VERSION 5.7 ;
BUSBITCHARS "[]" ;
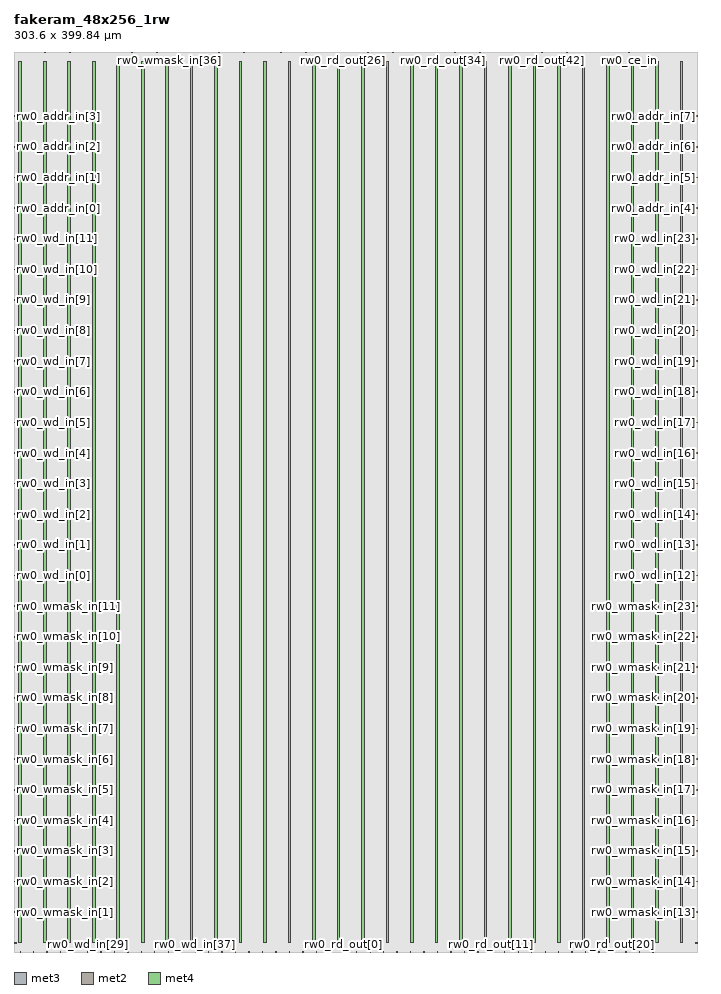
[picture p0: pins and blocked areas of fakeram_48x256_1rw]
MACRO fakeram_48x256_1rw
  FOREIGN fakeram_48x256_1rw 0 0 ;
  SYMMETRY X Y R90 ;
  SIZE 303.600 BY 399.840 ;
  CLASS BLOCK ;
  PIN rw0_wmask_in[0]
    DIRECTION INPUT ;
    USE SIGNAL ;
    SHAPE ABUTMENT ;
    PORT
      LAYER met3 ;
      RECT 0.000 3.930 0.900 4.230 ;
    END
  END rw0_wmask_in[0]
  PIN rw0_wmask_in[1]
    DIRECTION INPUT ;
    USE SIGNAL ;
    SHAPE ABUTMENT ;
    PORT
      LAYER met3 ;
      RECT 0.000 17.530 0.900 17.830 ;
    END
  END rw0_wmask_in[1]
  PIN rw0_wmask_in[2]
    DIRECTION INPUT ;
    USE SIGNAL ;
    SHAPE ABUTMENT ;
    PORT
      LAYER met3 ;
      RECT 0.000 31.130 0.900 31.430 ;
    END
  END rw0_wmask_in[2]
  PIN rw0_wmask_in[3]
    DIRECTION INPUT ;
    USE SIGNAL ;
    SHAPE ABUTMENT ;
    PORT
      LAYER met3 ;
      RECT 0.000 44.730 0.900 45.030 ;
    END
  END rw0_wmask_in[3]
  PIN rw0_wmask_in[4]
    DIRECTION INPUT ;
    USE SIGNAL ;
    SHAPE ABUTMENT ;
    PORT
      LAYER met3 ;
      RECT 0.000 58.330 0.900 58.630 ;
    END
  END rw0_wmask_in[4]
  PIN rw0_wmask_in[5]
    DIRECTION INPUT ;
    USE SIGNAL ;
    SHAPE ABUTMENT ;
    PORT
      LAYER met3 ;
      RECT 0.000 71.930 0.900 72.230 ;
    END
  END rw0_wmask_in[5]
  PIN rw0_wmask_in[6]
    DIRECTION INPUT ;
    USE SIGNAL ;
    SHAPE ABUTMENT ;
    PORT
      LAYER met3 ;
      RECT 0.000 85.530 0.900 85.830 ;
    END
  END rw0_wmask_in[6]
  PIN rw0_wmask_in[7]
    DIRECTION INPUT ;
    USE SIGNAL ;
    SHAPE ABUTMENT ;
    PORT
      LAYER met3 ;
      RECT 0.000 99.130 0.900 99.430 ;
    END
  END rw0_wmask_in[7]
  PIN rw0_wmask_in[8]
    DIRECTION INPUT ;
    USE SIGNAL ;
    SHAPE ABUTMENT ;
    PORT
      LAYER met3 ;
      RECT 0.000 112.730 0.900 113.030 ;
    END
  END rw0_wmask_in[8]
  PIN rw0_wmask_in[9]
    DIRECTION INPUT ;
    USE SIGNAL ;
    SHAPE ABUTMENT ;
    PORT
      LAYER met3 ;
      RECT 0.000 126.330 0.900 126.630 ;
    END
  END rw0_wmask_in[9]
  PIN rw0_wmask_in[10]
    DIRECTION INPUT ;
    USE SIGNAL ;
    SHAPE ABUTMENT ;
    PORT
      LAYER met3 ;
      RECT 0.000 139.930 0.900 140.230 ;
    END
  END rw0_wmask_in[10]
  PIN rw0_wmask_in[11]
    DIRECTION INPUT ;
    USE SIGNAL ;
    SHAPE ABUTMENT ;
    PORT
      LAYER met3 ;
      RECT 0.000 153.530 0.900 153.830 ;
    END
  END rw0_wmask_in[11]
  PIN rw0_wmask_in[12]
    DIRECTION INPUT ;
    USE SIGNAL ;
    SHAPE ABUTMENT ;
    PORT
      LAYER met3 ;
      RECT 302.700 3.930 303.600 4.230 ;
    END
  END rw0_wmask_in[12]
  PIN rw0_wmask_in[13]
    DIRECTION INPUT ;
    USE SIGNAL ;
    SHAPE ABUTMENT ;
    PORT
      LAYER met3 ;
      RECT 302.700 17.530 303.600 17.830 ;
    END
  END rw0_wmask_in[13]
  PIN rw0_wmask_in[14]
    DIRECTION INPUT ;
    USE SIGNAL ;
    SHAPE ABUTMENT ;
    PORT
      LAYER met3 ;
      RECT 302.700 31.130 303.600 31.430 ;
    END
  END rw0_wmask_in[14]
  PIN rw0_wmask_in[15]
    DIRECTION INPUT ;
    USE SIGNAL ;
    SHAPE ABUTMENT ;
    PORT
      LAYER met3 ;
      RECT 302.700 44.730 303.600 45.030 ;
    END
  END rw0_wmask_in[15]
  PIN rw0_wmask_in[16]
    DIRECTION INPUT ;
    USE SIGNAL ;
    SHAPE ABUTMENT ;
    PORT
      LAYER met3 ;
      RECT 302.700 58.330 303.600 58.630 ;
    END
  END rw0_wmask_in[16]
  PIN rw0_wmask_in[17]
    DIRECTION INPUT ;
    USE SIGNAL ;
    SHAPE ABUTMENT ;
    PORT
      LAYER met3 ;
      RECT 302.700 71.930 303.600 72.230 ;
    END
  END rw0_wmask_in[17]
  PIN rw0_wmask_in[18]
    DIRECTION INPUT ;
    USE SIGNAL ;
    SHAPE ABUTMENT ;
    PORT
      LAYER met3 ;
      RECT 302.700 85.530 303.600 85.830 ;
    END
  END rw0_wmask_in[18]
  PIN rw0_wmask_in[19]
    DIRECTION INPUT ;
    USE SIGNAL ;
    SHAPE ABUTMENT ;
    PORT
      LAYER met3 ;
      RECT 302.700 99.130 303.600 99.430 ;
    END
  END rw0_wmask_in[19]
  PIN rw0_wmask_in[20]
    DIRECTION INPUT ;
    USE SIGNAL ;
    SHAPE ABUTMENT ;
    PORT
      LAYER met3 ;
      RECT 302.700 112.730 303.600 113.030 ;
    END
  END rw0_wmask_in[20]
  PIN rw0_wmask_in[21]
    DIRECTION INPUT ;
    USE SIGNAL ;
    SHAPE ABUTMENT ;
    PORT
      LAYER met3 ;
      RECT 302.700 126.330 303.600 126.630 ;
    END
  END rw0_wmask_in[21]
  PIN rw0_wmask_in[22]
    DIRECTION INPUT ;
    USE SIGNAL ;
    SHAPE ABUTMENT ;
    PORT
      LAYER met3 ;
      RECT 302.700 139.930 303.600 140.230 ;
    END
  END rw0_wmask_in[22]
  PIN rw0_wmask_in[23]
    DIRECTION INPUT ;
    USE SIGNAL ;
    SHAPE ABUTMENT ;
    PORT
      LAYER met3 ;
      RECT 302.700 153.530 303.600 153.830 ;
    END
  END rw0_wmask_in[23]
  PIN rw0_wmask_in[24]
    DIRECTION INPUT ;
    USE SIGNAL ;
    SHAPE ABUTMENT ;
    PORT
      LAYER met2 ;
      RECT 2.690 399.420 2.830 399.840 ;
    END
  END rw0_wmask_in[24]
  PIN rw0_wmask_in[25]
    DIRECTION INPUT ;
    USE SIGNAL ;
    SHAPE ABUTMENT ;
    PORT
      LAYER met2 ;
      RECT 8.210 399.420 8.350 399.840 ;
    END
  END rw0_wmask_in[25]
  PIN rw0_wmask_in[26]
    DIRECTION INPUT ;
    USE SIGNAL ;
    SHAPE ABUTMENT ;
    PORT
      LAYER met2 ;
      RECT 13.730 399.420 13.870 399.840 ;
    END
  END rw0_wmask_in[26]
  PIN rw0_wmask_in[27]
    DIRECTION INPUT ;
    USE SIGNAL ;
    SHAPE ABUTMENT ;
    PORT
      LAYER met2 ;
      RECT 19.250 399.420 19.390 399.840 ;
    END
  END rw0_wmask_in[27]
  PIN rw0_wmask_in[28]
    DIRECTION INPUT ;
    USE SIGNAL ;
    SHAPE ABUTMENT ;
    PORT
      LAYER met2 ;
      RECT 24.770 399.420 24.910 399.840 ;
    END
  END rw0_wmask_in[28]
  PIN rw0_wmask_in[29]
    DIRECTION INPUT ;
    USE SIGNAL ;
    SHAPE ABUTMENT ;
    PORT
      LAYER met2 ;
      RECT 30.290 399.420 30.430 399.840 ;
    END
  END rw0_wmask_in[29]
  PIN rw0_wmask_in[30]
    DIRECTION INPUT ;
    USE SIGNAL ;
    SHAPE ABUTMENT ;
    PORT
      LAYER met2 ;
      RECT 35.810 399.420 35.950 399.840 ;
    END
  END rw0_wmask_in[30]
  PIN rw0_wmask_in[31]
    DIRECTION INPUT ;
    USE SIGNAL ;
    SHAPE ABUTMENT ;
    PORT
      LAYER met2 ;
      RECT 41.330 399.420 41.470 399.840 ;
    END
  END rw0_wmask_in[31]
  PIN rw0_wmask_in[32]
    DIRECTION INPUT ;
    USE SIGNAL ;
    SHAPE ABUTMENT ;
    PORT
      LAYER met2 ;
      RECT 46.850 399.420 46.990 399.840 ;
    END
  END rw0_wmask_in[32]
  PIN rw0_wmask_in[33]
    DIRECTION INPUT ;
    USE SIGNAL ;
    SHAPE ABUTMENT ;
    PORT
      LAYER met2 ;
      RECT 52.370 399.420 52.510 399.840 ;
    END
  END rw0_wmask_in[33]
  PIN rw0_wmask_in[34]
    DIRECTION INPUT ;
    USE SIGNAL ;
    SHAPE ABUTMENT ;
    PORT
      LAYER met2 ;
      RECT 57.890 399.420 58.030 399.840 ;
    END
  END rw0_wmask_in[34]
  PIN rw0_wmask_in[35]
    DIRECTION INPUT ;
    USE SIGNAL ;
    SHAPE ABUTMENT ;
    PORT
      LAYER met2 ;
      RECT 63.410 399.420 63.550 399.840 ;
    END
  END rw0_wmask_in[35]
  PIN rw0_wmask_in[36]
    DIRECTION INPUT ;
    USE SIGNAL ;
    SHAPE ABUTMENT ;
    PORT
      LAYER met2 ;
      RECT 68.930 399.420 69.070 399.840 ;
    END
  END rw0_wmask_in[36]
  PIN rw0_wmask_in[37]
    DIRECTION INPUT ;
    USE SIGNAL ;
    SHAPE ABUTMENT ;
    PORT
      LAYER met2 ;
      RECT 74.450 399.420 74.590 399.840 ;
    END
  END rw0_wmask_in[37]
  PIN rw0_wmask_in[38]
    DIRECTION INPUT ;
    USE SIGNAL ;
    SHAPE ABUTMENT ;
    PORT
      LAYER met2 ;
      RECT 79.970 399.420 80.110 399.840 ;
    END
  END rw0_wmask_in[38]
  PIN rw0_wmask_in[39]
    DIRECTION INPUT ;
    USE SIGNAL ;
    SHAPE ABUTMENT ;
    PORT
      LAYER met2 ;
      RECT 85.490 399.420 85.630 399.840 ;
    END
  END rw0_wmask_in[39]
  PIN rw0_wmask_in[40]
    DIRECTION INPUT ;
    USE SIGNAL ;
    SHAPE ABUTMENT ;
    PORT
      LAYER met2 ;
      RECT 91.010 399.420 91.150 399.840 ;
    END
  END rw0_wmask_in[40]
  PIN rw0_wmask_in[41]
    DIRECTION INPUT ;
    USE SIGNAL ;
    SHAPE ABUTMENT ;
    PORT
      LAYER met2 ;
      RECT 96.530 399.420 96.670 399.840 ;
    END
  END rw0_wmask_in[41]
  PIN rw0_wmask_in[42]
    DIRECTION INPUT ;
    USE SIGNAL ;
    SHAPE ABUTMENT ;
    PORT
      LAYER met2 ;
      RECT 102.050 399.420 102.190 399.840 ;
    END
  END rw0_wmask_in[42]
  PIN rw0_wmask_in[43]
    DIRECTION INPUT ;
    USE SIGNAL ;
    SHAPE ABUTMENT ;
    PORT
      LAYER met2 ;
      RECT 107.570 399.420 107.710 399.840 ;
    END
  END rw0_wmask_in[43]
  PIN rw0_wmask_in[44]
    DIRECTION INPUT ;
    USE SIGNAL ;
    SHAPE ABUTMENT ;
    PORT
      LAYER met2 ;
      RECT 113.090 399.420 113.230 399.840 ;
    END
  END rw0_wmask_in[44]
  PIN rw0_wmask_in[45]
    DIRECTION INPUT ;
    USE SIGNAL ;
    SHAPE ABUTMENT ;
    PORT
      LAYER met2 ;
      RECT 118.610 399.420 118.750 399.840 ;
    END
  END rw0_wmask_in[45]
  PIN rw0_wmask_in[46]
    DIRECTION INPUT ;
    USE SIGNAL ;
    SHAPE ABUTMENT ;
    PORT
      LAYER met2 ;
      RECT 124.130 399.420 124.270 399.840 ;
    END
  END rw0_wmask_in[46]
  PIN rw0_wmask_in[47]
    DIRECTION INPUT ;
    USE SIGNAL ;
    SHAPE ABUTMENT ;
    PORT
      LAYER met2 ;
      RECT 129.650 399.420 129.790 399.840 ;
    END
  END rw0_wmask_in[47]
  PIN rw0_wd_in[0]
    DIRECTION INPUT ;
    USE SIGNAL ;
    SHAPE ABUTMENT ;
    PORT
      LAYER met3 ;
      RECT 0.000 167.130 0.900 167.430 ;
    END
  END rw0_wd_in[0]
  PIN rw0_wd_in[1]
    DIRECTION INPUT ;
    USE SIGNAL ;
    SHAPE ABUTMENT ;
    PORT
      LAYER met3 ;
      RECT 0.000 180.730 0.900 181.030 ;
    END
  END rw0_wd_in[1]
  PIN rw0_wd_in[2]
    DIRECTION INPUT ;
    USE SIGNAL ;
    SHAPE ABUTMENT ;
    PORT
      LAYER met3 ;
      RECT 0.000 194.330 0.900 194.630 ;
    END
  END rw0_wd_in[2]
  PIN rw0_wd_in[3]
    DIRECTION INPUT ;
    USE SIGNAL ;
    SHAPE ABUTMENT ;
    PORT
      LAYER met3 ;
      RECT 0.000 207.930 0.900 208.230 ;
    END
  END rw0_wd_in[3]
  PIN rw0_wd_in[4]
    DIRECTION INPUT ;
    USE SIGNAL ;
    SHAPE ABUTMENT ;
    PORT
      LAYER met3 ;
      RECT 0.000 221.530 0.900 221.830 ;
    END
  END rw0_wd_in[4]
  PIN rw0_wd_in[5]
    DIRECTION INPUT ;
    USE SIGNAL ;
    SHAPE ABUTMENT ;
    PORT
      LAYER met3 ;
      RECT 0.000 235.130 0.900 235.430 ;
    END
  END rw0_wd_in[5]
  PIN rw0_wd_in[6]
    DIRECTION INPUT ;
    USE SIGNAL ;
    SHAPE ABUTMENT ;
    PORT
      LAYER met3 ;
      RECT 0.000 248.730 0.900 249.030 ;
    END
  END rw0_wd_in[6]
  PIN rw0_wd_in[7]
    DIRECTION INPUT ;
    USE SIGNAL ;
    SHAPE ABUTMENT ;
    PORT
      LAYER met3 ;
      RECT 0.000 262.330 0.900 262.630 ;
    END
  END rw0_wd_in[7]
  PIN rw0_wd_in[8]
    DIRECTION INPUT ;
    USE SIGNAL ;
    SHAPE ABUTMENT ;
    PORT
      LAYER met3 ;
      RECT 0.000 275.930 0.900 276.230 ;
    END
  END rw0_wd_in[8]
  PIN rw0_wd_in[9]
    DIRECTION INPUT ;
    USE SIGNAL ;
    SHAPE ABUTMENT ;
    PORT
      LAYER met3 ;
      RECT 0.000 289.530 0.900 289.830 ;
    END
  END rw0_wd_in[9]
  PIN rw0_wd_in[10]
    DIRECTION INPUT ;
    USE SIGNAL ;
    SHAPE ABUTMENT ;
    PORT
      LAYER met3 ;
      RECT 0.000 303.130 0.900 303.430 ;
    END
  END rw0_wd_in[10]
  PIN rw0_wd_in[11]
    DIRECTION INPUT ;
    USE SIGNAL ;
    SHAPE ABUTMENT ;
    PORT
      LAYER met3 ;
      RECT 0.000 316.730 0.900 317.030 ;
    END
  END rw0_wd_in[11]
  PIN rw0_wd_in[12]
    DIRECTION INPUT ;
    USE SIGNAL ;
    SHAPE ABUTMENT ;
    PORT
      LAYER met3 ;
      RECT 302.700 167.130 303.600 167.430 ;
    END
  END rw0_wd_in[12]
  PIN rw0_wd_in[13]
    DIRECTION INPUT ;
    USE SIGNAL ;
    SHAPE ABUTMENT ;
    PORT
      LAYER met3 ;
      RECT 302.700 180.730 303.600 181.030 ;
    END
  END rw0_wd_in[13]
  PIN rw0_wd_in[14]
    DIRECTION INPUT ;
    USE SIGNAL ;
    SHAPE ABUTMENT ;
    PORT
      LAYER met3 ;
      RECT 302.700 194.330 303.600 194.630 ;
    END
  END rw0_wd_in[14]
  PIN rw0_wd_in[15]
    DIRECTION INPUT ;
    USE SIGNAL ;
    SHAPE ABUTMENT ;
    PORT
      LAYER met3 ;
      RECT 302.700 207.930 303.600 208.230 ;
    END
  END rw0_wd_in[15]
  PIN rw0_wd_in[16]
    DIRECTION INPUT ;
    USE SIGNAL ;
    SHAPE ABUTMENT ;
    PORT
      LAYER met3 ;
      RECT 302.700 221.530 303.600 221.830 ;
    END
  END rw0_wd_in[16]
  PIN rw0_wd_in[17]
    DIRECTION INPUT ;
    USE SIGNAL ;
    SHAPE ABUTMENT ;
    PORT
      LAYER met3 ;
      RECT 302.700 235.130 303.600 235.430 ;
    END
  END rw0_wd_in[17]
  PIN rw0_wd_in[18]
    DIRECTION INPUT ;
    USE SIGNAL ;
    SHAPE ABUTMENT ;
    PORT
      LAYER met3 ;
      RECT 302.700 248.730 303.600 249.030 ;
    END
  END rw0_wd_in[18]
  PIN rw0_wd_in[19]
    DIRECTION INPUT ;
    USE SIGNAL ;
    SHAPE ABUTMENT ;
    PORT
      LAYER met3 ;
      RECT 302.700 262.330 303.600 262.630 ;
    END
  END rw0_wd_in[19]
  PIN rw0_wd_in[20]
    DIRECTION INPUT ;
    USE SIGNAL ;
    SHAPE ABUTMENT ;
    PORT
      LAYER met3 ;
      RECT 302.700 275.930 303.600 276.230 ;
    END
  END rw0_wd_in[20]
  PIN rw0_wd_in[21]
    DIRECTION INPUT ;
    USE SIGNAL ;
    SHAPE ABUTMENT ;
    PORT
      LAYER met3 ;
      RECT 302.700 289.530 303.600 289.830 ;
    END
  END rw0_wd_in[21]
  PIN rw0_wd_in[22]
    DIRECTION INPUT ;
    USE SIGNAL ;
    SHAPE ABUTMENT ;
    PORT
      LAYER met3 ;
      RECT 302.700 303.130 303.600 303.430 ;
    END
  END rw0_wd_in[22]
  PIN rw0_wd_in[23]
    DIRECTION INPUT ;
    USE SIGNAL ;
    SHAPE ABUTMENT ;
    PORT
      LAYER met3 ;
      RECT 302.700 316.730 303.600 317.030 ;
    END
  END rw0_wd_in[23]
  PIN rw0_wd_in[24]
    DIRECTION OUTPUT ;
    USE SIGNAL ;
    SHAPE ABUTMENT ;
    PORT
      LAYER met2 ;
      RECT 2.690 0.000 2.830 0.420 ;
    END
  END rw0_wd_in[24]
  PIN rw0_wd_in[25]
    DIRECTION OUTPUT ;
    USE SIGNAL ;
    SHAPE ABUTMENT ;
    PORT
      LAYER met2 ;
      RECT 8.670 0.000 8.810 0.420 ;
    END
  END rw0_wd_in[25]
  PIN rw0_wd_in[26]
    DIRECTION OUTPUT ;
    USE SIGNAL ;
    SHAPE ABUTMENT ;
    PORT
      LAYER met2 ;
      RECT 14.650 0.000 14.790 0.420 ;
    END
  END rw0_wd_in[26]
  PIN rw0_wd_in[27]
    DIRECTION OUTPUT ;
    USE SIGNAL ;
    SHAPE ABUTMENT ;
    PORT
      LAYER met2 ;
      RECT 20.630 0.000 20.770 0.420 ;
    END
  END rw0_wd_in[27]
  PIN rw0_wd_in[28]
    DIRECTION OUTPUT ;
    USE SIGNAL ;
    SHAPE ABUTMENT ;
    PORT
      LAYER met2 ;
      RECT 26.610 0.000 26.750 0.420 ;
    END
  END rw0_wd_in[28]
  PIN rw0_wd_in[29]
    DIRECTION OUTPUT ;
    USE SIGNAL ;
    SHAPE ABUTMENT ;
    PORT
      LAYER met2 ;
      RECT 32.590 0.000 32.730 0.420 ;
    END
  END rw0_wd_in[29]
  PIN rw0_wd_in[30]
    DIRECTION OUTPUT ;
    USE SIGNAL ;
    SHAPE ABUTMENT ;
    PORT
      LAYER met2 ;
      RECT 38.570 0.000 38.710 0.420 ;
    END
  END rw0_wd_in[30]
  PIN rw0_wd_in[31]
    DIRECTION OUTPUT ;
    USE SIGNAL ;
    SHAPE ABUTMENT ;
    PORT
      LAYER met2 ;
      RECT 44.550 0.000 44.690 0.420 ;
    END
  END rw0_wd_in[31]
  PIN rw0_wd_in[32]
    DIRECTION OUTPUT ;
    USE SIGNAL ;
    SHAPE ABUTMENT ;
    PORT
      LAYER met2 ;
      RECT 50.530 0.000 50.670 0.420 ;
    END
  END rw0_wd_in[32]
  PIN rw0_wd_in[33]
    DIRECTION OUTPUT ;
    USE SIGNAL ;
    SHAPE ABUTMENT ;
    PORT
      LAYER met2 ;
      RECT 56.510 0.000 56.650 0.420 ;
    END
  END rw0_wd_in[33]
  PIN rw0_wd_in[34]
    DIRECTION OUTPUT ;
    USE SIGNAL ;
    SHAPE ABUTMENT ;
    PORT
      LAYER met2 ;
      RECT 62.490 0.000 62.630 0.420 ;
    END
  END rw0_wd_in[34]
  PIN rw0_wd_in[35]
    DIRECTION OUTPUT ;
    USE SIGNAL ;
    SHAPE ABUTMENT ;
    PORT
      LAYER met2 ;
      RECT 68.470 0.000 68.610 0.420 ;
    END
  END rw0_wd_in[35]
  PIN rw0_wd_in[36]
    DIRECTION OUTPUT ;
    USE SIGNAL ;
    SHAPE ABUTMENT ;
    PORT
      LAYER met2 ;
      RECT 74.450 0.000 74.590 0.420 ;
    END
  END rw0_wd_in[36]
  PIN rw0_wd_in[37]
    DIRECTION OUTPUT ;
    USE SIGNAL ;
    SHAPE ABUTMENT ;
    PORT
      LAYER met2 ;
      RECT 80.430 0.000 80.570 0.420 ;
    END
  END rw0_wd_in[37]
  PIN rw0_wd_in[38]
    DIRECTION OUTPUT ;
    USE SIGNAL ;
    SHAPE ABUTMENT ;
    PORT
      LAYER met2 ;
      RECT 86.410 0.000 86.550 0.420 ;
    END
  END rw0_wd_in[38]
  PIN rw0_wd_in[39]
    DIRECTION OUTPUT ;
    USE SIGNAL ;
    SHAPE ABUTMENT ;
    PORT
      LAYER met2 ;
      RECT 92.390 0.000 92.530 0.420 ;
    END
  END rw0_wd_in[39]
  PIN rw0_wd_in[40]
    DIRECTION OUTPUT ;
    USE SIGNAL ;
    SHAPE ABUTMENT ;
    PORT
      LAYER met2 ;
      RECT 98.370 0.000 98.510 0.420 ;
    END
  END rw0_wd_in[40]
  PIN rw0_wd_in[41]
    DIRECTION OUTPUT ;
    USE SIGNAL ;
    SHAPE ABUTMENT ;
    PORT
      LAYER met2 ;
      RECT 104.350 0.000 104.490 0.420 ;
    END
  END rw0_wd_in[41]
  PIN rw0_wd_in[42]
    DIRECTION OUTPUT ;
    USE SIGNAL ;
    SHAPE ABUTMENT ;
    PORT
      LAYER met2 ;
      RECT 110.330 0.000 110.470 0.420 ;
    END
  END rw0_wd_in[42]
  PIN rw0_wd_in[43]
    DIRECTION OUTPUT ;
    USE SIGNAL ;
    SHAPE ABUTMENT ;
    PORT
      LAYER met2 ;
      RECT 116.310 0.000 116.450 0.420 ;
    END
  END rw0_wd_in[43]
  PIN rw0_wd_in[44]
    DIRECTION OUTPUT ;
    USE SIGNAL ;
    SHAPE ABUTMENT ;
    PORT
      LAYER met2 ;
      RECT 122.290 0.000 122.430 0.420 ;
    END
  END rw0_wd_in[44]
  PIN rw0_wd_in[45]
    DIRECTION OUTPUT ;
    USE SIGNAL ;
    SHAPE ABUTMENT ;
    PORT
      LAYER met2 ;
      RECT 128.270 0.000 128.410 0.420 ;
    END
  END rw0_wd_in[45]
  PIN rw0_wd_in[46]
    DIRECTION OUTPUT ;
    USE SIGNAL ;
    SHAPE ABUTMENT ;
    PORT
      LAYER met2 ;
      RECT 134.250 0.000 134.390 0.420 ;
    END
  END rw0_wd_in[46]
  PIN rw0_wd_in[47]
    DIRECTION OUTPUT ;
    USE SIGNAL ;
    SHAPE ABUTMENT ;
    PORT
      LAYER met2 ;
      RECT 140.230 0.000 140.370 0.420 ;
    END
  END rw0_wd_in[47]
  PIN rw0_rd_out[0]
    DIRECTION OUTPUT ;
    USE SIGNAL ;
    SHAPE ABUTMENT ;
    PORT
      LAYER met2 ;
      RECT 146.210 0.000 146.350 0.420 ;
    END
  END rw0_rd_out[0]
  PIN rw0_rd_out[1]
    DIRECTION OUTPUT ;
    USE SIGNAL ;
    SHAPE ABUTMENT ;
    PORT
      LAYER met2 ;
      RECT 152.190 0.000 152.330 0.420 ;
    END
  END rw0_rd_out[1]
  PIN rw0_rd_out[2]
    DIRECTION OUTPUT ;
    USE SIGNAL ;
    SHAPE ABUTMENT ;
    PORT
      LAYER met2 ;
      RECT 158.170 0.000 158.310 0.420 ;
    END
  END rw0_rd_out[2]
  PIN rw0_rd_out[3]
    DIRECTION OUTPUT ;
    USE SIGNAL ;
    SHAPE ABUTMENT ;
    PORT
      LAYER met2 ;
      RECT 164.150 0.000 164.290 0.420 ;
    END
  END rw0_rd_out[3]
  PIN rw0_rd_out[4]
    DIRECTION OUTPUT ;
    USE SIGNAL ;
    SHAPE ABUTMENT ;
    PORT
      LAYER met2 ;
      RECT 170.130 0.000 170.270 0.420 ;
    END
  END rw0_rd_out[4]
  PIN rw0_rd_out[5]
    DIRECTION OUTPUT ;
    USE SIGNAL ;
    SHAPE ABUTMENT ;
    PORT
      LAYER met2 ;
      RECT 176.110 0.000 176.250 0.420 ;
    END
  END rw0_rd_out[5]
  PIN rw0_rd_out[6]
    DIRECTION OUTPUT ;
    USE SIGNAL ;
    SHAPE ABUTMENT ;
    PORT
      LAYER met2 ;
      RECT 182.090 0.000 182.230 0.420 ;
    END
  END rw0_rd_out[6]
  PIN rw0_rd_out[7]
    DIRECTION OUTPUT ;
    USE SIGNAL ;
    SHAPE ABUTMENT ;
    PORT
      LAYER met2 ;
      RECT 188.070 0.000 188.210 0.420 ;
    END
  END rw0_rd_out[7]
  PIN rw0_rd_out[8]
    DIRECTION OUTPUT ;
    USE SIGNAL ;
    SHAPE ABUTMENT ;
    PORT
      LAYER met2 ;
      RECT 194.050 0.000 194.190 0.420 ;
    END
  END rw0_rd_out[8]
  PIN rw0_rd_out[9]
    DIRECTION OUTPUT ;
    USE SIGNAL ;
    SHAPE ABUTMENT ;
    PORT
      LAYER met2 ;
      RECT 200.030 0.000 200.170 0.420 ;
    END
  END rw0_rd_out[9]
  PIN rw0_rd_out[10]
    DIRECTION OUTPUT ;
    USE SIGNAL ;
    SHAPE ABUTMENT ;
    PORT
      LAYER met2 ;
      RECT 206.010 0.000 206.150 0.420 ;
    END
  END rw0_rd_out[10]
  PIN rw0_rd_out[11]
    DIRECTION OUTPUT ;
    USE SIGNAL ;
    SHAPE ABUTMENT ;
    PORT
      LAYER met2 ;
      RECT 211.990 0.000 212.130 0.420 ;
    END
  END rw0_rd_out[11]
  PIN rw0_rd_out[12]
    DIRECTION OUTPUT ;
    USE SIGNAL ;
    SHAPE ABUTMENT ;
    PORT
      LAYER met2 ;
      RECT 217.970 0.000 218.110 0.420 ;
    END
  END rw0_rd_out[12]
  PIN rw0_rd_out[13]
    DIRECTION OUTPUT ;
    USE SIGNAL ;
    SHAPE ABUTMENT ;
    PORT
      LAYER met2 ;
      RECT 223.950 0.000 224.090 0.420 ;
    END
  END rw0_rd_out[13]
  PIN rw0_rd_out[14]
    DIRECTION OUTPUT ;
    USE SIGNAL ;
    SHAPE ABUTMENT ;
    PORT
      LAYER met2 ;
      RECT 229.930 0.000 230.070 0.420 ;
    END
  END rw0_rd_out[14]
  PIN rw0_rd_out[15]
    DIRECTION OUTPUT ;
    USE SIGNAL ;
    SHAPE ABUTMENT ;
    PORT
      LAYER met2 ;
      RECT 235.910 0.000 236.050 0.420 ;
    END
  END rw0_rd_out[15]
  PIN rw0_rd_out[16]
    DIRECTION OUTPUT ;
    USE SIGNAL ;
    SHAPE ABUTMENT ;
    PORT
      LAYER met2 ;
      RECT 241.890 0.000 242.030 0.420 ;
    END
  END rw0_rd_out[16]
  PIN rw0_rd_out[17]
    DIRECTION OUTPUT ;
    USE SIGNAL ;
    SHAPE ABUTMENT ;
    PORT
      LAYER met2 ;
      RECT 247.870 0.000 248.010 0.420 ;
    END
  END rw0_rd_out[17]
  PIN rw0_rd_out[18]
    DIRECTION OUTPUT ;
    USE SIGNAL ;
    SHAPE ABUTMENT ;
    PORT
      LAYER met2 ;
      RECT 253.850 0.000 253.990 0.420 ;
    END
  END rw0_rd_out[18]
  PIN rw0_rd_out[19]
    DIRECTION OUTPUT ;
    USE SIGNAL ;
    SHAPE ABUTMENT ;
    PORT
      LAYER met2 ;
      RECT 259.830 0.000 259.970 0.420 ;
    END
  END rw0_rd_out[19]
  PIN rw0_rd_out[20]
    DIRECTION OUTPUT ;
    USE SIGNAL ;
    SHAPE ABUTMENT ;
    PORT
      LAYER met2 ;
      RECT 265.810 0.000 265.950 0.420 ;
    END
  END rw0_rd_out[20]
  PIN rw0_rd_out[21]
    DIRECTION OUTPUT ;
    USE SIGNAL ;
    SHAPE ABUTMENT ;
    PORT
      LAYER met2 ;
      RECT 271.790 0.000 271.930 0.420 ;
    END
  END rw0_rd_out[21]
  PIN rw0_rd_out[22]
    DIRECTION OUTPUT ;
    USE SIGNAL ;
    SHAPE ABUTMENT ;
    PORT
      LAYER met2 ;
      RECT 277.770 0.000 277.910 0.420 ;
    END
  END rw0_rd_out[22]
  PIN rw0_rd_out[23]
    DIRECTION OUTPUT ;
    USE SIGNAL ;
    SHAPE ABUTMENT ;
    PORT
      LAYER met2 ;
      RECT 283.750 0.000 283.890 0.420 ;
    END
  END rw0_rd_out[23]
  PIN rw0_rd_out[24]
    DIRECTION OUTPUT ;
    USE SIGNAL ;
    SHAPE ABUTMENT ;
    PORT
      LAYER met2 ;
      RECT 135.170 399.420 135.310 399.840 ;
    END
  END rw0_rd_out[24]
  PIN rw0_rd_out[25]
    DIRECTION OUTPUT ;
    USE SIGNAL ;
    SHAPE ABUTMENT ;
    PORT
      LAYER met2 ;
      RECT 140.690 399.420 140.830 399.840 ;
    END
  END rw0_rd_out[25]
  PIN rw0_rd_out[26]
    DIRECTION OUTPUT ;
    USE SIGNAL ;
    SHAPE ABUTMENT ;
    PORT
      LAYER met2 ;
      RECT 146.210 399.420 146.350 399.840 ;
    END
  END rw0_rd_out[26]
  PIN rw0_rd_out[27]
    DIRECTION OUTPUT ;
    USE SIGNAL ;
    SHAPE ABUTMENT ;
    PORT
      LAYER met2 ;
      RECT 151.730 399.420 151.870 399.840 ;
    END
  END rw0_rd_out[27]
  PIN rw0_rd_out[28]
    DIRECTION OUTPUT ;
    USE SIGNAL ;
    SHAPE ABUTMENT ;
    PORT
      LAYER met2 ;
      RECT 157.250 399.420 157.390 399.840 ;
    END
  END rw0_rd_out[28]
  PIN rw0_rd_out[29]
    DIRECTION OUTPUT ;
    USE SIGNAL ;
    SHAPE ABUTMENT ;
    PORT
      LAYER met2 ;
      RECT 162.770 399.420 162.910 399.840 ;
    END
  END rw0_rd_out[29]
  PIN rw0_rd_out[30]
    DIRECTION OUTPUT ;
    USE SIGNAL ;
    SHAPE ABUTMENT ;
    PORT
      LAYER met2 ;
      RECT 168.290 399.420 168.430 399.840 ;
    END
  END rw0_rd_out[30]
  PIN rw0_rd_out[31]
    DIRECTION OUTPUT ;
    USE SIGNAL ;
    SHAPE ABUTMENT ;
    PORT
      LAYER met2 ;
      RECT 173.810 399.420 173.950 399.840 ;
    END
  END rw0_rd_out[31]
  PIN rw0_rd_out[32]
    DIRECTION OUTPUT ;
    USE SIGNAL ;
    SHAPE ABUTMENT ;
    PORT
      LAYER met2 ;
      RECT 179.330 399.420 179.470 399.840 ;
    END
  END rw0_rd_out[32]
  PIN rw0_rd_out[33]
    DIRECTION OUTPUT ;
    USE SIGNAL ;
    SHAPE ABUTMENT ;
    PORT
      LAYER met2 ;
      RECT 184.850 399.420 184.990 399.840 ;
    END
  END rw0_rd_out[33]
  PIN rw0_rd_out[34]
    DIRECTION OUTPUT ;
    USE SIGNAL ;
    SHAPE ABUTMENT ;
    PORT
      LAYER met2 ;
      RECT 190.370 399.420 190.510 399.840 ;
    END
  END rw0_rd_out[34]
  PIN rw0_rd_out[35]
    DIRECTION OUTPUT ;
    USE SIGNAL ;
    SHAPE ABUTMENT ;
    PORT
      LAYER met2 ;
      RECT 195.890 399.420 196.030 399.840 ;
    END
  END rw0_rd_out[35]
  PIN rw0_rd_out[36]
    DIRECTION OUTPUT ;
    USE SIGNAL ;
    SHAPE ABUTMENT ;
    PORT
      LAYER met2 ;
      RECT 201.410 399.420 201.550 399.840 ;
    END
  END rw0_rd_out[36]
  PIN rw0_rd_out[37]
    DIRECTION OUTPUT ;
    USE SIGNAL ;
    SHAPE ABUTMENT ;
    PORT
      LAYER met2 ;
      RECT 206.930 399.420 207.070 399.840 ;
    END
  END rw0_rd_out[37]
  PIN rw0_rd_out[38]
    DIRECTION OUTPUT ;
    USE SIGNAL ;
    SHAPE ABUTMENT ;
    PORT
      LAYER met2 ;
      RECT 212.450 399.420 212.590 399.840 ;
    END
  END rw0_rd_out[38]
  PIN rw0_rd_out[39]
    DIRECTION OUTPUT ;
    USE SIGNAL ;
    SHAPE ABUTMENT ;
    PORT
      LAYER met2 ;
      RECT 217.970 399.420 218.110 399.840 ;
    END
  END rw0_rd_out[39]
  PIN rw0_rd_out[40]
    DIRECTION OUTPUT ;
    USE SIGNAL ;
    SHAPE ABUTMENT ;
    PORT
      LAYER met2 ;
      RECT 223.490 399.420 223.630 399.840 ;
    END
  END rw0_rd_out[40]
  PIN rw0_rd_out[41]
    DIRECTION OUTPUT ;
    USE SIGNAL ;
    SHAPE ABUTMENT ;
    PORT
      LAYER met2 ;
      RECT 229.010 399.420 229.150 399.840 ;
    END
  END rw0_rd_out[41]
  PIN rw0_rd_out[42]
    DIRECTION OUTPUT ;
    USE SIGNAL ;
    SHAPE ABUTMENT ;
    PORT
      LAYER met2 ;
      RECT 234.530 399.420 234.670 399.840 ;
    END
  END rw0_rd_out[42]
  PIN rw0_rd_out[43]
    DIRECTION OUTPUT ;
    USE SIGNAL ;
    SHAPE ABUTMENT ;
    PORT
      LAYER met2 ;
      RECT 240.050 399.420 240.190 399.840 ;
    END
  END rw0_rd_out[43]
  PIN rw0_rd_out[44]
    DIRECTION OUTPUT ;
    USE SIGNAL ;
    SHAPE ABUTMENT ;
    PORT
      LAYER met2 ;
      RECT 245.570 399.420 245.710 399.840 ;
    END
  END rw0_rd_out[44]
  PIN rw0_rd_out[45]
    DIRECTION OUTPUT ;
    USE SIGNAL ;
    SHAPE ABUTMENT ;
    PORT
      LAYER met2 ;
      RECT 251.090 399.420 251.230 399.840 ;
    END
  END rw0_rd_out[45]
  PIN rw0_rd_out[46]
    DIRECTION OUTPUT ;
    USE SIGNAL ;
    SHAPE ABUTMENT ;
    PORT
      LAYER met2 ;
      RECT 256.610 399.420 256.750 399.840 ;
    END
  END rw0_rd_out[46]
  PIN rw0_rd_out[47]
    DIRECTION OUTPUT ;
    USE SIGNAL ;
    SHAPE ABUTMENT ;
    PORT
      LAYER met2 ;
      RECT 262.130 399.420 262.270 399.840 ;
    END
  END rw0_rd_out[47]
  PIN rw0_addr_in[0]
    DIRECTION INPUT ;
    USE SIGNAL ;
    SHAPE ABUTMENT ;
    PORT
      LAYER met3 ;
      RECT 0.000 330.330 0.900 330.630 ;
    END
  END rw0_addr_in[0]
  PIN rw0_addr_in[1]
    DIRECTION INPUT ;
    USE SIGNAL ;
    SHAPE ABUTMENT ;
    PORT
      LAYER met3 ;
      RECT 0.000 343.930 0.900 344.230 ;
    END
  END rw0_addr_in[1]
  PIN rw0_addr_in[2]
    DIRECTION INPUT ;
    USE SIGNAL ;
    SHAPE ABUTMENT ;
    PORT
      LAYER met3 ;
      RECT 0.000 357.530 0.900 357.830 ;
    END
  END rw0_addr_in[2]
  PIN rw0_addr_in[3]
    DIRECTION INPUT ;
    USE SIGNAL ;
    SHAPE ABUTMENT ;
    PORT
      LAYER met3 ;
      RECT 0.000 371.130 0.900 371.430 ;
    END
  END rw0_addr_in[3]
  PIN rw0_addr_in[4]
    DIRECTION INPUT ;
    USE SIGNAL ;
    SHAPE ABUTMENT ;
    PORT
      LAYER met3 ;
      RECT 302.700 330.330 303.600 330.630 ;
    END
  END rw0_addr_in[4]
  PIN rw0_addr_in[5]
    DIRECTION INPUT ;
    USE SIGNAL ;
    SHAPE ABUTMENT ;
    PORT
      LAYER met3 ;
      RECT 302.700 343.930 303.600 344.230 ;
    END
  END rw0_addr_in[5]
  PIN rw0_addr_in[6]
    DIRECTION INPUT ;
    USE SIGNAL ;
    SHAPE ABUTMENT ;
    PORT
      LAYER met3 ;
      RECT 302.700 357.530 303.600 357.830 ;
    END
  END rw0_addr_in[6]
  PIN rw0_addr_in[7]
    DIRECTION INPUT ;
    USE SIGNAL ;
    SHAPE ABUTMENT ;
    PORT
      LAYER met3 ;
      RECT 302.700 371.130 303.600 371.430 ;
    END
  END rw0_addr_in[7]
  PIN rw0_we_in
    DIRECTION INPUT ;
    USE SIGNAL ;
    SHAPE ABUTMENT ;
    PORT
      LAYER met2 ;
      RECT 267.650 399.420 267.790 399.840 ;
    END
  END rw0_we_in
  PIN rw0_ce_in
    DIRECTION INPUT ;
    USE SIGNAL ;
    SHAPE ABUTMENT ;
    PORT
      LAYER met2 ;
      RECT 273.170 399.420 273.310 399.840 ;
    END
  END rw0_ce_in
  PIN rw0_clk
    DIRECTION INPUT ;
    USE SIGNAL ;
    SHAPE ABUTMENT ;
    PORT
      LAYER met2 ;
      RECT 278.690 399.420 278.830 399.840 ;
    END
  END rw0_clk
  PIN VSS
    DIRECTION INOUT ;
    USE GROUND ;
    PORT
      LAYER met4 ;
      RECT 2.160 4.080 3.360 395.760 ;
      RECT 13.040 4.080 14.240 395.760 ;
      RECT 23.920 4.080 25.120 395.760 ;
      RECT 34.800 4.080 36.000 395.760 ;
      RECT 45.680 4.080 46.880 395.760 ;
      RECT 56.560 4.080 57.760 395.760 ;
      RECT 67.440 4.080 68.640 395.760 ;
      RECT 78.320 4.080 79.520 395.760 ;
      RECT 89.200 4.080 90.400 395.760 ;
      RECT 100.080 4.080 101.280 395.760 ;
      RECT 110.960 4.080 112.160 395.760 ;
      RECT 121.840 4.080 123.040 395.760 ;
      RECT 132.720 4.080 133.920 395.760 ;
      RECT 143.600 4.080 144.800 395.760 ;
      RECT 154.480 4.080 155.680 395.760 ;
      RECT 165.360 4.080 166.560 395.760 ;
      RECT 176.240 4.080 177.440 395.760 ;
      RECT 187.120 4.080 188.320 395.760 ;
      RECT 198.000 4.080 199.200 395.760 ;
      RECT 208.880 4.080 210.080 395.760 ;
      RECT 219.760 4.080 220.960 395.760 ;
      RECT 230.640 4.080 231.840 395.760 ;
      RECT 241.520 4.080 242.720 395.760 ;
      RECT 252.400 4.080 253.600 395.760 ;
      RECT 263.280 4.080 264.480 395.760 ;
      RECT 274.160 4.080 275.360 395.760 ;
      RECT 285.040 4.080 286.240 395.760 ;
      RECT 295.920 4.080 297.120 395.760 ;
    END
  END VSS
  PIN VDD
    DIRECTION INOUT ;
    USE POWER ;
    PORT
      LAYER met4 ;
      RECT 2.160 4.080 3.360 395.760 ;
      RECT 13.040 4.080 14.240 395.760 ;
      RECT 23.920 4.080 25.120 395.760 ;
      RECT 34.800 4.080 36.000 395.760 ;
      RECT 45.680 4.080 46.880 395.760 ;
      RECT 56.560 4.080 57.760 395.760 ;
      RECT 67.440 4.080 68.640 395.760 ;
      RECT 78.320 4.080 79.520 395.760 ;
      RECT 89.200 4.080 90.400 395.760 ;
      RECT 100.080 4.080 101.280 395.760 ;
      RECT 110.960 4.080 112.160 395.760 ;
      RECT 121.840 4.080 123.040 395.760 ;
      RECT 132.720 4.080 133.920 395.760 ;
      RECT 143.600 4.080 144.800 395.760 ;
      RECT 154.480 4.080 155.680 395.760 ;
      RECT 165.360 4.080 166.560 395.760 ;
      RECT 176.240 4.080 177.440 395.760 ;
      RECT 187.120 4.080 188.320 395.760 ;
      RECT 198.000 4.080 199.200 395.760 ;
      RECT 208.880 4.080 210.080 395.760 ;
      RECT 219.760 4.080 220.960 395.760 ;
      RECT 230.640 4.080 231.840 395.760 ;
      RECT 241.520 4.080 242.720 395.760 ;
      RECT 252.400 4.080 253.600 395.760 ;
      RECT 263.280 4.080 264.480 395.760 ;
      RECT 274.160 4.080 275.360 395.760 ;
      RECT 285.040 4.080 286.240 395.760 ;
      RECT 295.920 4.080 297.120 395.760 ;
    END
  END VDD
  OBS
    LAYER met1 ;
    RECT 0 0 303.600 399.840 ;
    LAYER met2 ;
    RECT 0 0 303.600 399.840 ;
    LAYER met3 ;
    RECT 0 0 303.600 399.840 ;
    LAYER met4 ;
    RECT 0 0 303.600 399.840 ;
  END
END fakeram_48x256_1rw

END LIBRARY
